VERSION 5.7 ;
  NOWIREEXTENSIONATPIN ON ;
  DIVIDERCHAR "/" ;
  BUSBITCHARS "[]" ;
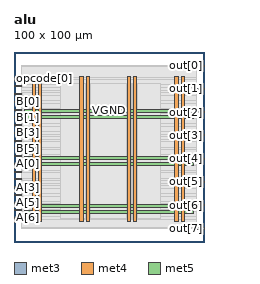
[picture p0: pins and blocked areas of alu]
MACRO alu
  CLASS BLOCK ;
  FOREIGN alu ;
  ORIGIN 0.000 0.000 ;
  SIZE 100.000 BY 100.000 ;
  PIN A[0]
    DIRECTION INPUT ;
    USE SIGNAL ;
    ANTENNAGATEAREA 0.159000 ;
    PORT
      LAYER met3 ;
        RECT 0.000 40.840 4.000 41.440 ;
    END
  END A[0]
  PIN A[1]
    DIRECTION INPUT ;
    USE SIGNAL ;
    ANTENNAGATEAREA 0.159000 ;
    PORT
      LAYER met3 ;
        RECT 0.000 36.760 4.000 37.360 ;
    END
  END A[1]
  PIN A[2]
    DIRECTION INPUT ;
    USE SIGNAL ;
    ANTENNAGATEAREA 0.247500 ;
    PORT
      LAYER met3 ;
        RECT 0.000 32.680 4.000 33.280 ;
    END
  END A[2]
  PIN A[3]
    DIRECTION INPUT ;
    USE SIGNAL ;
    ANTENNAGATEAREA 0.213000 ;
    PORT
      LAYER met3 ;
        RECT 0.000 28.600 4.000 29.200 ;
    END
  END A[3]
  PIN A[4]
    DIRECTION INPUT ;
    USE SIGNAL ;
    ANTENNAGATEAREA 0.159000 ;
    PORT
      LAYER met3 ;
        RECT 0.000 24.520 4.000 25.120 ;
    END
  END A[4]
  PIN A[5]
    DIRECTION INPUT ;
    USE SIGNAL ;
    ANTENNAGATEAREA 0.213000 ;
    PORT
      LAYER met3 ;
        RECT 0.000 20.440 4.000 21.040 ;
    END
  END A[5]
  PIN A[6]
    DIRECTION INPUT ;
    USE SIGNAL ;
    ANTENNAGATEAREA 0.213000 ;
    PORT
      LAYER met3 ;
        RECT 0.000 16.360 4.000 16.960 ;
    END
  END A[6]
  PIN A[7]
    DIRECTION INPUT ;
    USE SIGNAL ;
    ANTENNAGATEAREA 0.213000 ;
    PORT
      LAYER met3 ;
        RECT 0.000 12.280 4.000 12.880 ;
    END
  END A[7]
  PIN B[0]
    DIRECTION INPUT ;
    USE SIGNAL ;
    ANTENNAGATEAREA 0.159000 ;
    PORT
      LAYER met3 ;
        RECT 0.000 73.480 4.000 74.080 ;
    END
  END B[0]
  PIN B[1]
    DIRECTION INPUT ;
    USE SIGNAL ;
    ANTENNAGATEAREA 0.213000 ;
    PORT
      LAYER met3 ;
        RECT 0.000 69.400 4.000 70.000 ;
    END
  END B[1]
  PIN B[2]
    DIRECTION INPUT ;
    USE SIGNAL ;
    ANTENNAGATEAREA 0.247500 ;
    PORT
      LAYER met3 ;
        RECT 0.000 65.320 4.000 65.920 ;
    END
  END B[2]
  PIN B[3]
    DIRECTION INPUT ;
    USE SIGNAL ;
    ANTENNAGATEAREA 0.213000 ;
    PORT
      LAYER met3 ;
        RECT 0.000 61.240 4.000 61.840 ;
    END
  END B[3]
  PIN B[4]
    DIRECTION INPUT ;
    USE SIGNAL ;
    ANTENNAGATEAREA 0.213000 ;
    PORT
      LAYER met3 ;
        RECT 0.000 57.160 4.000 57.760 ;
    END
  END B[4]
  PIN B[5]
    DIRECTION INPUT ;
    USE SIGNAL ;
    ANTENNAGATEAREA 0.159000 ;
    PORT
      LAYER met3 ;
        RECT 0.000 53.080 4.000 53.680 ;
    END
  END B[5]
  PIN B[6]
    DIRECTION INPUT ;
    USE SIGNAL ;
    ANTENNAGATEAREA 0.159000 ;
    PORT
      LAYER met3 ;
        RECT 0.000 49.000 4.000 49.600 ;
    END
  END B[6]
  PIN B[7]
    DIRECTION INPUT ;
    USE SIGNAL ;
    ANTENNAGATEAREA 0.126000 ;
    PORT
      LAYER met3 ;
        RECT 0.000 44.920 4.000 45.520 ;
    END
  END B[7]
  PIN VGND
    DIRECTION INOUT ;
    USE GROUND ;
    PORT
      LAYER met4 ;
        RECT 13.020 10.640 14.620 87.280 ;
    END
    PORT
      LAYER met4 ;
        RECT 38.020 10.640 39.620 87.280 ;
    END
    PORT
      LAYER met4 ;
        RECT 63.020 10.640 64.620 87.280 ;
    END
    PORT
      LAYER met4 ;
        RECT 88.020 10.640 89.620 87.280 ;
    END
    PORT
      LAYER met5 ;
        RECT 5.280 18.380 94.540 19.980 ;
    END
    PORT
      LAYER met5 ;
        RECT 5.280 43.380 94.540 44.980 ;
    END
    PORT
      LAYER met5 ;
        RECT 5.280 68.380 94.540 69.980 ;
    END
  END VGND
  PIN VPWR
    DIRECTION INOUT ;
    USE POWER ;
    PORT
      LAYER met4 ;
        RECT 9.720 10.640 11.320 87.280 ;
    END
    PORT
      LAYER met4 ;
        RECT 34.720 10.640 36.320 87.280 ;
    END
    PORT
      LAYER met4 ;
        RECT 59.720 10.640 61.320 87.280 ;
    END
    PORT
      LAYER met4 ;
        RECT 84.720 10.640 86.320 87.280 ;
    END
    PORT
      LAYER met5 ;
        RECT 5.280 15.080 94.540 16.680 ;
    END
    PORT
      LAYER met5 ;
        RECT 5.280 40.080 94.540 41.680 ;
    END
    PORT
      LAYER met5 ;
        RECT 5.280 65.080 94.540 66.680 ;
    END
  END VPWR
  PIN opcode[0]
    DIRECTION INPUT ;
    USE SIGNAL ;
    ANTENNAGATEAREA 0.159000 ;
    PORT
      LAYER met3 ;
        RECT 0.000 85.720 4.000 86.320 ;
    END
  END opcode[0]
  PIN opcode[1]
    DIRECTION INPUT ;
    USE SIGNAL ;
    ANTENNAGATEAREA 0.247500 ;
    PORT
      LAYER met3 ;
        RECT 0.000 81.640 4.000 82.240 ;
    END
  END opcode[1]
  PIN opcode[2]
    DIRECTION INPUT ;
    USE SIGNAL ;
    ANTENNAGATEAREA 0.213000 ;
    PORT
      LAYER met3 ;
        RECT 0.000 77.560 4.000 78.160 ;
    END
  END opcode[2]
  PIN out[0]
    DIRECTION OUTPUT ;
    USE SIGNAL ;
    ANTENNADIFFAREA 0.445500 ;
    PORT
      LAYER met3 ;
        RECT 96.000 92.520 100.000 93.120 ;
    END
  END out[0]
  PIN out[1]
    DIRECTION OUTPUT ;
    USE SIGNAL ;
    ANTENNADIFFAREA 0.445500 ;
    PORT
      LAYER met3 ;
        RECT 96.000 80.280 100.000 80.880 ;
    END
  END out[1]
  PIN out[2]
    DIRECTION OUTPUT ;
    USE SIGNAL ;
    ANTENNADIFFAREA 0.445500 ;
    PORT
      LAYER met3 ;
        RECT 96.000 68.040 100.000 68.640 ;
    END
  END out[2]
  PIN out[3]
    DIRECTION OUTPUT ;
    USE SIGNAL ;
    ANTENNADIFFAREA 0.445500 ;
    PORT
      LAYER met3 ;
        RECT 96.000 55.800 100.000 56.400 ;
    END
  END out[3]
  PIN out[4]
    DIRECTION OUTPUT ;
    USE SIGNAL ;
    ANTENNADIFFAREA 0.445500 ;
    PORT
      LAYER met3 ;
        RECT 96.000 43.560 100.000 44.160 ;
    END
  END out[4]
  PIN out[5]
    DIRECTION OUTPUT ;
    USE SIGNAL ;
    ANTENNADIFFAREA 0.445500 ;
    PORT
      LAYER met3 ;
        RECT 96.000 31.320 100.000 31.920 ;
    END
  END out[5]
  PIN out[6]
    DIRECTION OUTPUT ;
    USE SIGNAL ;
    ANTENNADIFFAREA 0.445500 ;
    PORT
      LAYER met3 ;
        RECT 96.000 19.080 100.000 19.680 ;
    END
  END out[6]
  PIN out[7]
    DIRECTION OUTPUT ;
    USE SIGNAL ;
    ANTENNADIFFAREA 0.445500 ;
    PORT
      LAYER met3 ;
        RECT 96.000 6.840 100.000 7.440 ;
    END
  END out[7]
  OBS
      LAYER nwell ;
        RECT 5.330 10.795 94.490 87.125 ;
      LAYER li1 ;
        RECT 5.520 10.795 94.300 87.125 ;
      LAYER met1 ;
        RECT 4.210 10.240 94.300 87.280 ;
      LAYER met2 ;
        RECT 4.230 6.955 93.740 93.005 ;
      LAYER met3 ;
        RECT 3.990 92.120 95.600 92.985 ;
        RECT 3.990 86.720 96.000 92.120 ;
        RECT 4.400 85.320 96.000 86.720 ;
        RECT 3.990 82.640 96.000 85.320 ;
        RECT 4.400 81.280 96.000 82.640 ;
        RECT 4.400 81.240 95.600 81.280 ;
        RECT 3.990 79.880 95.600 81.240 ;
        RECT 3.990 78.560 96.000 79.880 ;
        RECT 4.400 77.160 96.000 78.560 ;
        RECT 3.990 74.480 96.000 77.160 ;
        RECT 4.400 73.080 96.000 74.480 ;
        RECT 3.990 70.400 96.000 73.080 ;
        RECT 4.400 69.040 96.000 70.400 ;
        RECT 4.400 69.000 95.600 69.040 ;
        RECT 3.990 67.640 95.600 69.000 ;
        RECT 3.990 66.320 96.000 67.640 ;
        RECT 4.400 64.920 96.000 66.320 ;
        RECT 3.990 62.240 96.000 64.920 ;
        RECT 4.400 60.840 96.000 62.240 ;
        RECT 3.990 58.160 96.000 60.840 ;
        RECT 4.400 56.800 96.000 58.160 ;
        RECT 4.400 56.760 95.600 56.800 ;
        RECT 3.990 55.400 95.600 56.760 ;
        RECT 3.990 54.080 96.000 55.400 ;
        RECT 4.400 52.680 96.000 54.080 ;
        RECT 3.990 50.000 96.000 52.680 ;
        RECT 4.400 48.600 96.000 50.000 ;
        RECT 3.990 45.920 96.000 48.600 ;
        RECT 4.400 44.560 96.000 45.920 ;
        RECT 4.400 44.520 95.600 44.560 ;
        RECT 3.990 43.160 95.600 44.520 ;
        RECT 3.990 41.840 96.000 43.160 ;
        RECT 4.400 40.440 96.000 41.840 ;
        RECT 3.990 37.760 96.000 40.440 ;
        RECT 4.400 36.360 96.000 37.760 ;
        RECT 3.990 33.680 96.000 36.360 ;
        RECT 4.400 32.320 96.000 33.680 ;
        RECT 4.400 32.280 95.600 32.320 ;
        RECT 3.990 30.920 95.600 32.280 ;
        RECT 3.990 29.600 96.000 30.920 ;
        RECT 4.400 28.200 96.000 29.600 ;
        RECT 3.990 25.520 96.000 28.200 ;
        RECT 4.400 24.120 96.000 25.520 ;
        RECT 3.990 21.440 96.000 24.120 ;
        RECT 4.400 20.080 96.000 21.440 ;
        RECT 4.400 20.040 95.600 20.080 ;
        RECT 3.990 18.680 95.600 20.040 ;
        RECT 3.990 17.360 96.000 18.680 ;
        RECT 4.400 15.960 96.000 17.360 ;
        RECT 3.990 13.280 96.000 15.960 ;
        RECT 4.400 11.880 96.000 13.280 ;
        RECT 3.990 7.840 96.000 11.880 ;
        RECT 3.990 6.975 95.600 7.840 ;
      LAYER met4 ;
        RECT 24.215 12.415 34.320 83.465 ;
        RECT 36.720 12.415 37.620 83.465 ;
        RECT 40.020 12.415 59.320 83.465 ;
        RECT 61.720 12.415 62.620 83.465 ;
        RECT 65.020 12.415 76.985 83.465 ;
  END
END alu
END LIBRARY

